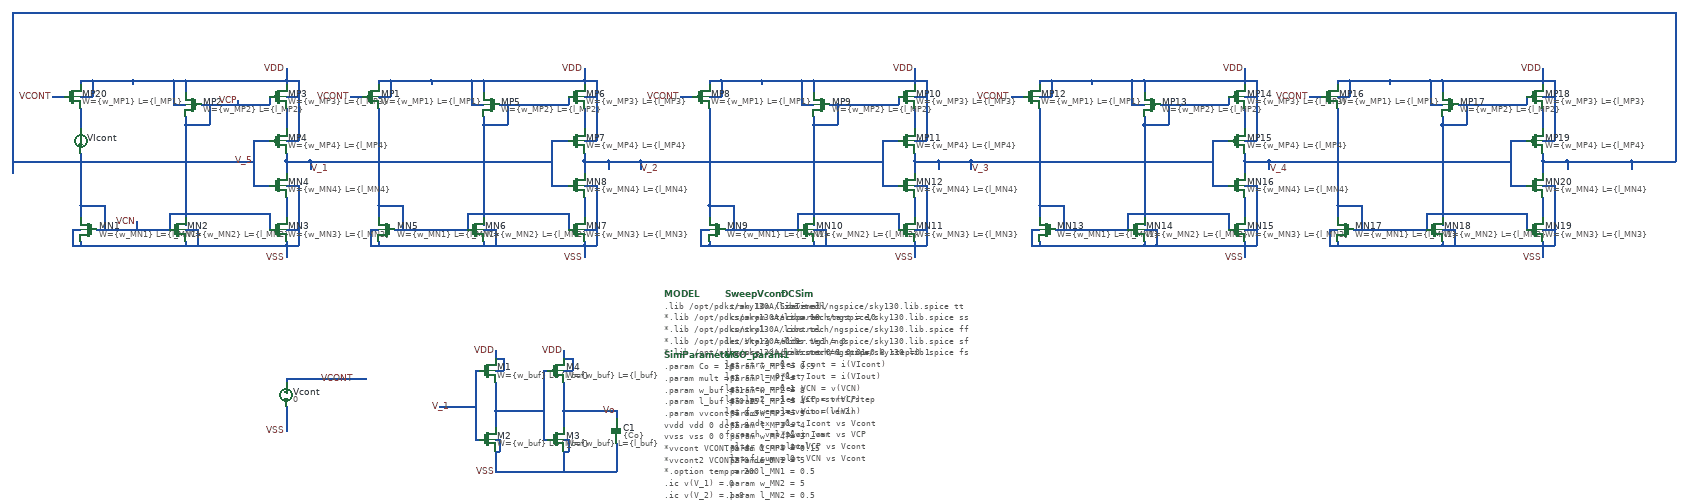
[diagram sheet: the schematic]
v {xschem version=3.4.5 file_version=1.2
}
G {}
K {}
V {}
S {}
E {}
N -2160 -960 -2160 -930 {
lab=VDD}
N -2160 -520 -2160 -490 {
lab=VSS}
N -1990 -190 -1960 -190 {
lab=VCONT}
N -1780 -120 -1750 -120 {
lab=V_1}
N -1750 -120 -1720 -120 {
lab=V_1}
N -1720 -120 -1690 -120 {
lab=V_1}
N -2160 -190 -1990 -190 {
lab=VCONT}
N -2160 -190 -2160 -180 {
lab=VCONT}
N -2160 -120 -2160 -80 {
lab=VSS}
N -2160 -80 -2160 -60 {
lab=VSS}
N -2240 -780 -2200 -780 { lab=V_5}
N -2240 -780 -2240 -670 { lab=V_5}
N -2240 -670 -2200 -670 { lab=V_5}
N -2160 -730 -2160 -700 { lab=V_1}
N -2160 -860 -2160 -810 { lab=#net1}
N -2160 -780 -2130 -780 { lab=VDD}
N -2160 -670 -2130 -670 { lab=VSS}
N -2130 -670 -2130 -560 { lab=VSS}
N -2160 -640 -2160 -590 { lab=#net2}
N -2160 -730 -2100 -730 { lab=V_1}
N -2160 -520 -2160 -510 {
lab=VSS}
N -2160 -930 -2160 -920 {
lab=VDD}
N -2160 -930 -2130 -930 {
lab=VDD}
N -2130 -890 -2130 -780 {
lab=VDD}
N -2160 -890 -2130 -890 {
lab=VDD}
N -2160 -520 -2130 -520 {
lab=VSS}
N -2130 -560 -2130 -520 {
lab=VSS}
N -2160 -560 -2130 -560 {
lab=VSS}
N -2350 -870 -2200 -870 {
lab=VCP}
N -2410 -910 -2410 -900 {
lab=VDD}
N -2410 -930 -2160 -930 {
lab=VDD}
N -2410 -820 -2410 -570 {
lab=VCP}
N -2380 -520 -2160 -520 {
lab=VSS}
N -2410 -530 -2410 -520 {
lab=VSS}
N -2610 -560 -2450 -560 {
lab=VCN}
N -2670 -520 -2410 -520 {
lab=VSS}
N -2670 -530 -2670 -520 {
lab=VSS}
N -2670 -620 -2670 -590 {
lab=VCN}
N -2440 -930 -2410 -930 {
lab=VDD}
N -2670 -930 -2670 -920 {
lab=VDD}
N -2610 -620 -2610 -560 {
lab=VCN}
N -2670 -620 -2610 -620 {
lab=VCN}
N -2410 -820 -2350 -820 {
lab=VCP}
N -2350 -870 -2350 -820 {
lab=VCP}
N -2740 -890 -2710 -890 {
lab=VCONT}
N -2410 -560 -2380 -560 {
lab=VSS}
N -2380 -560 -2380 -520 {
lab=VSS}
N -2450 -600 -2450 -560 {
lab=VCN}
N -2450 -600 -2200 -600 {
lab=VCN}
N -2200 -600 -2200 -560 {
lab=VCN}
N -2690 -560 -2670 -560 {
lab=VSS}
N -2690 -560 -2690 -520 {
lab=VSS}
N -2690 -520 -2670 -520 {
lab=VSS}
N -2670 -890 -2640 -890 {
lab=VDD}
N -2640 -930 -2640 -890 {
lab=VDD}
N -2440 -870 -2410 -870 {
lab=VDD}
N -2440 -910 -2440 -870 {
lab=VDD}
N -2160 -750 -2160 -730 { lab=V_1}
N -2160 -940 -2160 -930 {
lab=VDD}
N -2130 -930 -2130 -890 {
lab=VDD}
N -2160 -530 -2160 -520 {
lab=VSS}
N -2630 -560 -2610 -560 {
lab=VCN}
N -2410 -840 -2410 -820 {
lab=VCP}
N -2370 -870 -2350 -870 {
lab=VCP}
N -2410 -520 -2380 -520 {
lab=VSS}
N -2670 -930 -2640 -930 {
lab=VDD}
N -2510 -930 -2440 -930 {
lab=VDD}
N -2540 -930 -2540 -920 {
lab=VDD}
N -2540 -930 -2510 -930 {
lab=VDD}
N -2640 -930 -2540 -930 {
lab=VDD}
N -2670 -860 -2670 -830 {
lab=#net3}
N -2200 -890 -2200 -870 {
lab=VCP}
N -2440 -930 -2440 -910 {
lab=VDD}
N -2410 -930 -2410 -910 {
lab=VDD}
N -510 -730 -450 -730 { lab=V_3}
N 1120 -730 1180 -730 { lab=V_5}
N -2100 -730 -2100 -710 {
lab=V_1}
N -1280 -730 -1280 -710 {
lab=V_2}
N 1180 -730 1180 -710 {
lab=V_5}
N 1180 -730 1290 -730 {
lab=V_5}
N 1290 -1090 1290 -730 {
lab=V_5}
N -2840 -1100 1290 -1100 {
lab=V_5}
N -2840 -1100 -2840 -700 {
lab=V_5}
N -2840 -730 -2240 -730 {
lab=V_5}
N -1420 -960 -1420 -930 {
lab=VDD}
N -1420 -520 -1420 -490 {
lab=VSS}
N -1500 -780 -1460 -780 { lab=V_1}
N -1500 -780 -1500 -670 { lab=V_1}
N -1500 -670 -1460 -670 { lab=V_1}
N -1420 -730 -1420 -700 { lab=V_2}
N -1420 -860 -1420 -810 { lab=#net4}
N -1420 -780 -1390 -780 { lab=VDD}
N -1420 -670 -1390 -670 { lab=VSS}
N -1390 -670 -1390 -560 { lab=VSS}
N -1420 -640 -1420 -590 { lab=#net5}
N -1420 -730 -1360 -730 { lab=V_2}
N -1420 -520 -1420 -510 {
lab=VSS}
N -1420 -930 -1420 -920 {
lab=VDD}
N -1420 -930 -1390 -930 {
lab=VDD}
N -1390 -890 -1390 -780 {
lab=VDD}
N -1420 -890 -1390 -890 {
lab=VDD}
N -1420 -520 -1390 -520 {
lab=VSS}
N -1390 -560 -1390 -520 {
lab=VSS}
N -1420 -560 -1390 -560 {
lab=VSS}
N -1610 -870 -1460 -870 {
lab=#net6}
N -1670 -910 -1670 -900 {
lab=VDD}
N -1670 -930 -1420 -930 {
lab=VDD}
N -1670 -820 -1670 -570 {
lab=#net6}
N -1640 -520 -1420 -520 {
lab=VSS}
N -1670 -530 -1670 -520 {
lab=VSS}
N -1870 -560 -1710 -560 {
lab=#net7}
N -1930 -520 -1670 -520 {
lab=VSS}
N -1930 -530 -1930 -520 {
lab=VSS}
N -1930 -620 -1930 -590 {
lab=#net7}
N -1700 -930 -1670 -930 {
lab=VDD}
N -1930 -930 -1930 -920 {
lab=VDD}
N -1870 -620 -1870 -560 {
lab=#net7}
N -1930 -620 -1870 -620 {
lab=#net7}
N -1670 -820 -1610 -820 {
lab=#net6}
N -1610 -870 -1610 -820 {
lab=#net6}
N -2000 -890 -1970 -890 {
lab=VCONT}
N -1670 -560 -1640 -560 {
lab=VSS}
N -1640 -560 -1640 -520 {
lab=VSS}
N -1710 -600 -1710 -560 {
lab=#net7}
N -1710 -600 -1460 -600 {
lab=#net7}
N -1460 -600 -1460 -560 {
lab=#net7}
N -1950 -560 -1930 -560 {
lab=VSS}
N -1950 -560 -1950 -520 {
lab=VSS}
N -1950 -520 -1930 -520 {
lab=VSS}
N -1930 -890 -1900 -890 {
lab=VDD}
N -1900 -930 -1900 -890 {
lab=VDD}
N -1700 -870 -1670 -870 {
lab=VDD}
N -1700 -910 -1700 -870 {
lab=VDD}
N -1420 -750 -1420 -730 { lab=V_2}
N -1420 -940 -1420 -930 {
lab=VDD}
N -1390 -930 -1390 -890 {
lab=VDD}
N -1420 -530 -1420 -520 {
lab=VSS}
N -1890 -560 -1870 -560 {
lab=#net7}
N -1930 -830 -1930 -620 {
lab=#net7}
N -1670 -840 -1670 -820 {
lab=#net6}
N -1630 -870 -1610 -870 {
lab=#net6}
N -1670 -520 -1640 -520 {
lab=VSS}
N -1930 -930 -1900 -930 {
lab=VDD}
N -1770 -930 -1700 -930 {
lab=VDD}
N -1800 -930 -1800 -920 {
lab=VDD}
N -1800 -930 -1770 -930 {
lab=VDD}
N -1900 -930 -1800 -930 {
lab=VDD}
N -1930 -860 -1930 -830 {
lab=#net7}
N -1460 -890 -1460 -870 {
lab=#net6}
N -1700 -930 -1700 -910 {
lab=VDD}
N -1670 -930 -1670 -910 {
lab=VDD}
N -1360 -730 -1360 -710 {
lab=V_2}
N -2100 -730 -1500 -730 {
lab=V_1}
N -1360 -730 -1280 -730 {
lab=V_2}
N -460 -730 -460 -710 {
lab=V_3}
N -600 -960 -600 -930 {
lab=VDD}
N -600 -520 -600 -490 {
lab=VSS}
N -680 -780 -640 -780 { lab=V_2}
N -680 -780 -680 -670 { lab=V_2}
N -680 -670 -640 -670 { lab=V_2}
N -600 -730 -600 -700 { lab=V_3}
N -600 -860 -600 -810 { lab=#net8}
N -600 -780 -570 -780 { lab=VDD}
N -600 -670 -570 -670 { lab=VSS}
N -570 -670 -570 -560 { lab=VSS}
N -600 -640 -600 -590 { lab=#net9}
N -600 -730 -540 -730 { lab=V_3}
N -600 -520 -600 -510 {
lab=VSS}
N -600 -930 -600 -920 {
lab=VDD}
N -600 -930 -570 -930 {
lab=VDD}
N -570 -890 -570 -780 {
lab=VDD}
N -600 -890 -570 -890 {
lab=VDD}
N -600 -520 -570 -520 {
lab=VSS}
N -570 -560 -570 -520 {
lab=VSS}
N -600 -560 -570 -560 {
lab=VSS}
N -790 -870 -640 -870 {
lab=#net10}
N -850 -910 -850 -900 {
lab=VDD}
N -850 -930 -600 -930 {
lab=VDD}
N -850 -820 -850 -570 {
lab=#net10}
N -820 -520 -600 -520 {
lab=VSS}
N -850 -530 -850 -520 {
lab=VSS}
N -1050 -560 -890 -560 {
lab=#net11}
N -1110 -520 -850 -520 {
lab=VSS}
N -1110 -530 -1110 -520 {
lab=VSS}
N -1110 -620 -1110 -590 {
lab=#net11}
N -880 -930 -850 -930 {
lab=VDD}
N -1110 -930 -1110 -920 {
lab=VDD}
N -1050 -620 -1050 -560 {
lab=#net11}
N -1110 -620 -1050 -620 {
lab=#net11}
N -850 -820 -790 -820 {
lab=#net10}
N -790 -870 -790 -820 {
lab=#net10}
N -1180 -890 -1150 -890 {
lab=VCONT}
N -850 -560 -820 -560 {
lab=VSS}
N -820 -560 -820 -520 {
lab=VSS}
N -890 -600 -890 -560 {
lab=#net11}
N -890 -600 -640 -600 {
lab=#net11}
N -640 -600 -640 -560 {
lab=#net11}
N -1130 -560 -1110 -560 {
lab=VSS}
N -1130 -560 -1130 -520 {
lab=VSS}
N -1130 -520 -1110 -520 {
lab=VSS}
N -1110 -890 -1080 -890 {
lab=VDD}
N -1080 -930 -1080 -890 {
lab=VDD}
N -880 -870 -850 -870 {
lab=VDD}
N -880 -910 -880 -870 {
lab=VDD}
N -600 -750 -600 -730 { lab=V_3}
N -600 -940 -600 -930 {
lab=VDD}
N -570 -930 -570 -890 {
lab=VDD}
N -600 -530 -600 -520 {
lab=VSS}
N -1070 -560 -1050 -560 {
lab=#net11}
N -1110 -830 -1110 -620 {
lab=#net11}
N -850 -840 -850 -820 {
lab=#net10}
N -810 -870 -790 -870 {
lab=#net10}
N -850 -520 -820 -520 {
lab=VSS}
N -1110 -930 -1080 -930 {
lab=VDD}
N -950 -930 -880 -930 {
lab=VDD}
N -980 -930 -980 -920 {
lab=VDD}
N -980 -930 -950 -930 {
lab=VDD}
N -1080 -930 -980 -930 {
lab=VDD}
N -1110 -860 -1110 -830 {
lab=#net11}
N -640 -890 -640 -870 {
lab=#net10}
N -880 -930 -880 -910 {
lab=VDD}
N -850 -930 -850 -910 {
lab=VDD}
N -540 -730 -540 -710 {
lab=V_3}
N -1280 -730 -680 -730 {
lab=V_2}
N -540 -730 -460 -730 {
lab=V_3}
N 220 -960 220 -930 {
lab=VDD}
N 220 -520 220 -490 {
lab=VSS}
N 140 -780 180 -780 { lab=V_3}
N 140 -780 140 -670 { lab=V_3}
N 140 -670 180 -670 { lab=V_3}
N 220 -730 220 -700 { lab=V_4}
N 220 -860 220 -810 { lab=#net12}
N 220 -780 250 -780 { lab=VDD}
N 220 -670 250 -670 { lab=VSS}
N 250 -670 250 -560 { lab=VSS}
N 220 -640 220 -590 { lab=#net13}
N 220 -730 280 -730 { lab=V_4}
N 220 -520 220 -510 {
lab=VSS}
N 220 -930 220 -920 {
lab=VDD}
N 220 -930 250 -930 {
lab=VDD}
N 250 -890 250 -780 {
lab=VDD}
N 220 -890 250 -890 {
lab=VDD}
N 220 -520 250 -520 {
lab=VSS}
N 250 -560 250 -520 {
lab=VSS}
N 220 -560 250 -560 {
lab=VSS}
N 30 -870 180 -870 {
lab=#net14}
N -30 -910 -30 -900 {
lab=VDD}
N -30 -930 220 -930 {
lab=VDD}
N -30 -820 -30 -570 {
lab=#net14}
N 0 -520 220 -520 {
lab=VSS}
N -30 -530 -30 -520 {
lab=VSS}
N -230 -560 -70 -560 {
lab=#net15}
N -290 -520 -30 -520 {
lab=VSS}
N -290 -530 -290 -520 {
lab=VSS}
N -290 -620 -290 -590 {
lab=#net15}
N -60 -930 -30 -930 {
lab=VDD}
N -290 -930 -290 -920 {
lab=VDD}
N -230 -620 -230 -560 {
lab=#net15}
N -290 -620 -230 -620 {
lab=#net15}
N -30 -820 30 -820 {
lab=#net14}
N 30 -870 30 -820 {
lab=#net14}
N -360 -890 -330 -890 {
lab=VCONT}
N -30 -560 0 -560 {
lab=VSS}
N 0 -560 0 -520 {
lab=VSS}
N -70 -600 -70 -560 {
lab=#net15}
N -70 -600 180 -600 {
lab=#net15}
N 180 -600 180 -560 {
lab=#net15}
N -310 -560 -290 -560 {
lab=VSS}
N -310 -560 -310 -520 {
lab=VSS}
N -310 -520 -290 -520 {
lab=VSS}
N -290 -890 -260 -890 {
lab=VDD}
N -260 -930 -260 -890 {
lab=VDD}
N -60 -870 -30 -870 {
lab=VDD}
N -60 -910 -60 -870 {
lab=VDD}
N 220 -750 220 -730 { lab=V_4}
N 220 -940 220 -930 {
lab=VDD}
N 250 -930 250 -890 {
lab=VDD}
N 220 -530 220 -520 {
lab=VSS}
N -250 -560 -230 -560 {
lab=#net15}
N -290 -830 -290 -620 {
lab=#net15}
N -30 -840 -30 -820 {
lab=#net14}
N 10 -870 30 -870 {
lab=#net14}
N -30 -520 0 -520 {
lab=VSS}
N -290 -930 -260 -930 {
lab=VDD}
N -130 -930 -60 -930 {
lab=VDD}
N -160 -930 -160 -920 {
lab=VDD}
N -160 -930 -130 -930 {
lab=VDD}
N -260 -930 -160 -930 {
lab=VDD}
N -290 -860 -290 -830 {
lab=#net15}
N 180 -890 180 -870 {
lab=#net14}
N -60 -930 -60 -910 {
lab=VDD}
N -30 -930 -30 -910 {
lab=VDD}
N 280 -730 280 -710 {
lab=V_4}
N -460 -730 140 -730 {
lab=V_3}
N 960 -960 960 -930 {
lab=VDD}
N 960 -520 960 -490 {
lab=VSS}
N 880 -780 920 -780 { lab=V_4}
N 880 -780 880 -670 { lab=V_4}
N 880 -670 920 -670 { lab=V_4}
N 960 -730 960 -700 { lab=V_5}
N 960 -860 960 -810 { lab=#net16}
N 960 -780 990 -780 { lab=VDD}
N 960 -670 990 -670 { lab=VSS}
N 990 -670 990 -560 { lab=VSS}
N 960 -640 960 -590 { lab=#net17}
N 960 -730 1020 -730 { lab=V_5}
N 960 -520 960 -510 {
lab=VSS}
N 960 -930 960 -920 {
lab=VDD}
N 960 -930 990 -930 {
lab=VDD}
N 990 -890 990 -780 {
lab=VDD}
N 960 -890 990 -890 {
lab=VDD}
N 960 -520 990 -520 {
lab=VSS}
N 990 -560 990 -520 {
lab=VSS}
N 960 -560 990 -560 {
lab=VSS}
N 770 -870 920 -870 {
lab=#net18}
N 710 -910 710 -900 {
lab=VDD}
N 710 -930 960 -930 {
lab=VDD}
N 710 -820 710 -570 {
lab=#net18}
N 740 -520 960 -520 {
lab=VSS}
N 710 -530 710 -520 {
lab=VSS}
N 510 -560 670 -560 {
lab=#net19}
N 450 -520 710 -520 {
lab=VSS}
N 450 -530 450 -520 {
lab=VSS}
N 450 -620 450 -590 {
lab=#net19}
N 680 -930 710 -930 {
lab=VDD}
N 450 -930 450 -920 {
lab=VDD}
N 510 -620 510 -560 {
lab=#net19}
N 450 -620 510 -620 {
lab=#net19}
N 710 -820 770 -820 {
lab=#net18}
N 770 -870 770 -820 {
lab=#net18}
N 380 -890 410 -890 {
lab=VCONT}
N 710 -560 740 -560 {
lab=VSS}
N 740 -560 740 -520 {
lab=VSS}
N 670 -600 670 -560 {
lab=#net19}
N 670 -600 920 -600 {
lab=#net19}
N 920 -600 920 -560 {
lab=#net19}
N 430 -560 450 -560 {
lab=VSS}
N 430 -560 430 -520 {
lab=VSS}
N 430 -520 450 -520 {
lab=VSS}
N 450 -890 480 -890 {
lab=VDD}
N 480 -930 480 -890 {
lab=VDD}
N 680 -870 710 -870 {
lab=VDD}
N 680 -910 680 -870 {
lab=VDD}
N 960 -750 960 -730 { lab=V_5}
N 960 -940 960 -930 {
lab=VDD}
N 990 -930 990 -890 {
lab=VDD}
N 960 -530 960 -520 {
lab=VSS}
N 490 -560 510 -560 {
lab=#net19}
N 450 -830 450 -620 {
lab=#net19}
N 710 -840 710 -820 {
lab=#net18}
N 750 -870 770 -870 {
lab=#net18}
N 710 -520 740 -520 {
lab=VSS}
N 450 -930 480 -930 {
lab=VDD}
N 610 -930 680 -930 {
lab=VDD}
N 580 -930 580 -920 {
lab=VDD}
N 580 -930 610 -930 {
lab=VDD}
N 480 -930 580 -930 {
lab=VDD}
N 450 -860 450 -830 {
lab=#net19}
N 920 -890 920 -870 {
lab=#net18}
N 680 -930 680 -910 {
lab=VDD}
N 710 -930 710 -910 {
lab=VDD}
N 1020 -730 1020 -710 {
lab=V_5}
N 280 -730 880 -730 {
lab=V_4}
N 1020 -730 1120 -730 {
lab=V_5}
N 1290 -1100 1290 -1070 {
lab=V_5}
N -1640 -110 -1640 -70 {
lab=#net20}
N -1640 -180 -1640 -110 {
lab=#net20}
N -1640 -40 -1630 -40 {
lab=VSS}
N -1630 -40 -1630 -10 {
lab=VSS}
N -1640 -10 -1630 -10 {
lab=VSS}
N -1640 -210 -1620 -210 {
lab=VDD}
N -1620 -240 -1620 -210 {
lab=VDD}
N -1640 -240 -1620 -240 {
lab=VDD}
N -1640 -110 -1630 -110 {
lab=#net20}
N -1690 -210 -1680 -210 {
lab=V_1}
N -1690 -210 -1690 -40 {
lab=V_1}
N -1690 -40 -1680 -40 {
lab=V_1}
N -1640 -10 -1640 40 {
lab=VSS}
N -1640 -260 -1640 -240 {
lab=VDD}
N -1340 -30 -1340 40 {
lab=VSS}
N -1340 -110 -1340 -90 {
lab=Vo}
N -1470 -110 -1470 -70 {
lab=Vo}
N -1470 -180 -1470 -110 {
lab=Vo}
N -1470 -40 -1460 -40 {
lab=VSS}
N -1460 -40 -1460 -10 {
lab=VSS}
N -1470 -10 -1460 -10 {
lab=VSS}
N -1470 -210 -1450 -210 {
lab=VDD}
N -1450 -240 -1450 -210 {
lab=VDD}
N -1470 -240 -1450 -240 {
lab=VDD}
N -1470 -110 -1460 -110 {
lab=Vo}
N -1520 -210 -1510 -210 {
lab=#net20}
N -1520 -210 -1520 -40 {
lab=#net20}
N -1520 -40 -1510 -40 {
lab=#net20}
N -1470 -10 -1470 40 {
lab=VSS}
N -1470 -260 -1470 -240 {
lab=VDD}
N -1630 -110 -1520 -110 {
lab=#net20}
N -1470 -110 -1340 -110 {
lab=Vo}
N -1640 40 -1340 40 {
lab=VSS}
N -2670 -830 -2670 -810 {
lab=#net3}
N -2670 -750 -2670 -620 {
lab=VCN}
N -2530 -580 -2530 -560 {
lab=VCN}
N -2280 -880 -2280 -870 {
lab=VCP}
C {devices/lab_pin.sym} -2160 -960 1 0 {name=p4 sig_type=std_logic lab=VDD}
C {devices/lab_pin.sym} -2160 -490 3 0 {name=p5 sig_type=std_logic lab=VSS}
C {devices/lab_pin.sym} -1990 -190 1 0 {name=p6 sig_type=std_logic lab=VCONT}
C {devices/lab_pin.sym} -1750 -120 1 0 {name=p7 sig_type=std_logic lab=V_1}
C {vsource.sym} -2160 -150 0 0 {name=Vcont value=0 savecurrent=false}
C {devices/lab_pin.sym} -2160 -60 3 0 {name=p11 sig_type=std_logic lab=VSS}
C {sky130_fd_pr/pfet_01v8.sym} -2690 -890 0 0 {name=MP20
W= \{w_MP1\}
L= \{l_MP1\}
nf=1
mult=1
ad="'int((nf+1)/2) * W/nf * 0.29'" 
pd="'2*int((nf+1)/2) * (W/nf + 0.29)'"
as="'int((nf+2)/2) * W/nf * 0.29'" 
ps="'2*int((nf+2)/2) * (W/nf + 0.29)'"
nrd="'0.29 / W'" nrs="'0.29 / W'"
sa=0 sb=0 sd=0
model=pfet_01v8
spiceprefix=X
}
C {sky130_fd_pr/pfet_01v8.sym} -2390 -870 0 1 {name=MP2
*W= 8
W = \{w_MP2\}
*L= 4
L = \{l_MP2\}
nf=1
mult=1
ad="'int((nf+1)/2) * W/nf * 0.29'" 
pd="'2*int((nf+1)/2) * (W/nf + 0.29)'"
as="'int((nf+2)/2) * W/nf * 0.29'" 
ps="'2*int((nf+2)/2) * (W/nf + 0.29)'"
nrd="'0.29 / W'" nrs="'0.29 / W'"
sa=0 sb=0 sd=0
model=pfet_01v8
spiceprefix=X
}
C {sky130_fd_pr/pfet_01v8.sym} -2180 -890 0 0 {name=MP3
*W=5
W = \{w_MP3\}
*L=4
L = \{l_MP3\}
nf=1
mult=1
ad="'int((nf+1)/2) * W/nf * 0.29'" 
pd="'2*int((nf+1)/2) * (W/nf + 0.29)'"
as="'int((nf+2)/2) * W/nf * 0.29'" 
ps="'2*int((nf+2)/2) * (W/nf + 0.29)'"
nrd="'0.29 / W'" nrs="'0.29 / W'"
sa=0 sb=0 sd=0
model=pfet_01v8
spiceprefix=X
}
C {sky130_fd_pr/pfet_01v8.sym} -2180 -780 0 0 {name=MP4
*W=5
W = \{w_MP4\}
L = \{l_MP4\}
*L=5
nf=1
mult=1
ad="'int((nf+1)/2) * W/nf * 0.29'" 
pd="'2*int((nf+1)/2) * (W/nf + 0.29)'"
as="'int((nf+2)/2) * W/nf * 0.29'" 
ps="'2*int((nf+2)/2) * (W/nf + 0.29)'"
nrd="'0.29 / W'" nrs="'0.29 / W'"
sa=0 sb=0 sd=0
model=pfet_01v8
spiceprefix=X
}
C {sky130_fd_pr/nfet_01v8.sym} -2650 -560 0 1 {name=MN1
*W=5
W = \{w_MN1\}
*L=0.5
L = \{l_MN1\}
nf=1
mult=1
ad="'int((nf+1)/2) * W/nf * 0.29'" 
pd="'2*int((nf+1)/2) * (W/nf + 0.29)'"
as="'int((nf+2)/2) * W/nf * 0.29'" 
ps="'2*int((nf+2)/2) * (W/nf + 0.29)'"
nrd="'0.29 / W'" nrs="'0.29 / W'"
sa=0 sb=0 sd=0
model=nfet_01v8
spiceprefix=X
}
C {sky130_fd_pr/nfet_01v8.sym} -2430 -560 0 0 {name=MN2
*W=5
W = \{w_MN2\}
*L=0.5
L = \{l_MN2\}
nf=1
mult=1
ad="'int((nf+1)/2) * W/nf * 0.29'" 
pd="'2*int((nf+1)/2) * (W/nf + 0.29)'"
as="'int((nf+2)/2) * W/nf * 0.29'" 
ps="'2*int((nf+2)/2) * (W/nf + 0.29)'"
nrd="'0.29 / W'" nrs="'0.29 / W'"
sa=0 sb=0 sd=0
model=nfet_01v8
spiceprefix=X
}
C {sky130_fd_pr/nfet_01v8.sym} -2180 -560 0 0 {name=MN3
*W=3
W = \{w_MN3\}
*L=0.5
L = \{l_MN3\}
nf=1
mult=1
ad="'int((nf+1)/2) * W/nf * 0.29'" 
pd="'2*int((nf+1)/2) * (W/nf + 0.29)'"
as="'int((nf+2)/2) * W/nf * 0.29'" 
ps="'2*int((nf+2)/2) * (W/nf + 0.29)'"
nrd="'0.29 / W'" nrs="'0.29 / W'"
sa=0 sb=0 sd=0
model=nfet_01v8
spiceprefix=X
}
C {sky130_fd_pr/nfet_01v8.sym} -2180 -670 0 0 {name=MN4
*W=2
W = \{w_MN4\}
*L=5
L = \{l_MN4\}
nf=1
mult=1
ad="'int((nf+1)/2) * W/nf * 0.29'" 
pd="'2*int((nf+1)/2) * (W/nf + 0.29)'"
as="'int((nf+2)/2) * W/nf * 0.29'" 
ps="'2*int((nf+2)/2) * (W/nf + 0.29)'"
nrd="'0.29 / W'" nrs="'0.29 / W'"
sa=0 sb=0 sd=0
model=nfet_01v8
spiceprefix=X
}
C {devices/lab_pin.sym} -2740 -890 0 0 {name=p27 sig_type=std_logic lab=VCONT}
C {devices/lab_pin.sym} -2100 -710 2 0 {name=p21 sig_type=std_logic lab=V_1}
C {devices/lab_pin.sym} -2240 -730 0 0 {name=p22 sig_type=std_logic lab=V_5}
C {devices/lab_pin.sym} -1280 -710 2 0 {name=p29 sig_type=std_logic lab=V_2}
C {devices/lab_pin.sym} -460 -710 2 0 {name=p35 sig_type=std_logic lab=V_3}
C {devices/lab_pin.sym} 280 -710 2 0 {name=p41 sig_type=std_logic lab=V_4}
C {devices/lab_pin.sym} -1420 -960 1 0 {name=p1 sig_type=std_logic lab=VDD}
C {devices/lab_pin.sym} -1420 -490 3 0 {name=p12 sig_type=std_logic lab=VSS}
C {sky130_fd_pr/pfet_01v8.sym} -1950 -890 0 0 {name=MP1
W= \{w_MP1\}
L= \{l_MP1\}
nf=1
mult=1
ad="'int((nf+1)/2) * W/nf * 0.29'" 
pd="'2*int((nf+1)/2) * (W/nf + 0.29)'"
as="'int((nf+2)/2) * W/nf * 0.29'" 
ps="'2*int((nf+2)/2) * (W/nf + 0.29)'"
nrd="'0.29 / W'" nrs="'0.29 / W'"
sa=0 sb=0 sd=0
model=pfet_01v8
spiceprefix=X
}
C {sky130_fd_pr/pfet_01v8.sym} -1650 -870 0 1 {name=MP5
*W= 8
W = \{w_MP2\}
*L= 4
L = \{l_MP2\}
nf=1
mult=1
ad="'int((nf+1)/2) * W/nf * 0.29'" 
pd="'2*int((nf+1)/2) * (W/nf + 0.29)'"
as="'int((nf+2)/2) * W/nf * 0.29'" 
ps="'2*int((nf+2)/2) * (W/nf + 0.29)'"
nrd="'0.29 / W'" nrs="'0.29 / W'"
sa=0 sb=0 sd=0
model=pfet_01v8
spiceprefix=X
}
C {sky130_fd_pr/pfet_01v8.sym} -1440 -890 0 0 {name=MP6
*W=5
W = \{w_MP3\}
*L=4
L = \{l_MP3\}
nf=1
mult=1
ad="'int((nf+1)/2) * W/nf * 0.29'" 
pd="'2*int((nf+1)/2) * (W/nf + 0.29)'"
as="'int((nf+2)/2) * W/nf * 0.29'" 
ps="'2*int((nf+2)/2) * (W/nf + 0.29)'"
nrd="'0.29 / W'" nrs="'0.29 / W'"
sa=0 sb=0 sd=0
model=pfet_01v8
spiceprefix=X
}
C {sky130_fd_pr/pfet_01v8.sym} -1440 -780 0 0 {name=MP7
*W=5
W = \{w_MP4\}
L = \{l_MP4\}
*L=5
nf=1
mult=1
ad="'int((nf+1)/2) * W/nf * 0.29'" 
pd="'2*int((nf+1)/2) * (W/nf + 0.29)'"
as="'int((nf+2)/2) * W/nf * 0.29'" 
ps="'2*int((nf+2)/2) * (W/nf + 0.29)'"
nrd="'0.29 / W'" nrs="'0.29 / W'"
sa=0 sb=0 sd=0
model=pfet_01v8
spiceprefix=X
}
C {sky130_fd_pr/nfet_01v8.sym} -1910 -560 0 1 {name=MN5
*W=5
W = \{w_MN1\}
*L=0.5
L = \{l_MN1\}
nf=1
mult=1
ad="'int((nf+1)/2) * W/nf * 0.29'" 
pd="'2*int((nf+1)/2) * (W/nf + 0.29)'"
as="'int((nf+2)/2) * W/nf * 0.29'" 
ps="'2*int((nf+2)/2) * (W/nf + 0.29)'"
nrd="'0.29 / W'" nrs="'0.29 / W'"
sa=0 sb=0 sd=0
model=nfet_01v8
spiceprefix=X
}
C {sky130_fd_pr/nfet_01v8.sym} -1690 -560 0 0 {name=MN6
*W=5
W = \{w_MN2\}
*L=0.5
L = \{l_MN2\}
nf=1
mult=1
ad="'int((nf+1)/2) * W/nf * 0.29'" 
pd="'2*int((nf+1)/2) * (W/nf + 0.29)'"
as="'int((nf+2)/2) * W/nf * 0.29'" 
ps="'2*int((nf+2)/2) * (W/nf + 0.29)'"
nrd="'0.29 / W'" nrs="'0.29 / W'"
sa=0 sb=0 sd=0
model=nfet_01v8
spiceprefix=X
}
C {sky130_fd_pr/nfet_01v8.sym} -1440 -560 0 0 {name=MN7
*W=3
W = \{w_MN3\}
*L=0.5
L = \{l_MN3\}
nf=1
mult=1
ad="'int((nf+1)/2) * W/nf * 0.29'" 
pd="'2*int((nf+1)/2) * (W/nf + 0.29)'"
as="'int((nf+2)/2) * W/nf * 0.29'" 
ps="'2*int((nf+2)/2) * (W/nf + 0.29)'"
nrd="'0.29 / W'" nrs="'0.29 / W'"
sa=0 sb=0 sd=0
model=nfet_01v8
spiceprefix=X
}
C {sky130_fd_pr/nfet_01v8.sym} -1440 -670 0 0 {name=MN8
*W=2
W = \{w_MN4\}
*L=5
L = \{l_MN4\}
nf=1
mult=1
ad="'int((nf+1)/2) * W/nf * 0.29'" 
pd="'2*int((nf+1)/2) * (W/nf + 0.29)'"
as="'int((nf+2)/2) * W/nf * 0.29'" 
ps="'2*int((nf+2)/2) * (W/nf + 0.29)'"
nrd="'0.29 / W'" nrs="'0.29 / W'"
sa=0 sb=0 sd=0
model=nfet_01v8
spiceprefix=X
}
C {devices/lab_pin.sym} -2000 -890 0 0 {name=p13 sig_type=std_logic lab=VCONT}
C {devices/lab_pin.sym} -600 -960 1 0 {name=p15 sig_type=std_logic lab=VDD}
C {devices/lab_pin.sym} -600 -490 3 0 {name=p16 sig_type=std_logic lab=VSS}
C {sky130_fd_pr/pfet_01v8.sym} -1130 -890 0 0 {name=MP8
W= \{w_MP1\}
L= \{l_MP1\}
nf=1
mult=1
ad="'int((nf+1)/2) * W/nf * 0.29'" 
pd="'2*int((nf+1)/2) * (W/nf + 0.29)'"
as="'int((nf+2)/2) * W/nf * 0.29'" 
ps="'2*int((nf+2)/2) * (W/nf + 0.29)'"
nrd="'0.29 / W'" nrs="'0.29 / W'"
sa=0 sb=0 sd=0
model=pfet_01v8
spiceprefix=X
}
C {sky130_fd_pr/pfet_01v8.sym} -830 -870 0 1 {name=MP9
*W= 8
W = \{w_MP2\}
*L= 4
L = \{l_MP2\}
nf=1
mult=1
ad="'int((nf+1)/2) * W/nf * 0.29'" 
pd="'2*int((nf+1)/2) * (W/nf + 0.29)'"
as="'int((nf+2)/2) * W/nf * 0.29'" 
ps="'2*int((nf+2)/2) * (W/nf + 0.29)'"
nrd="'0.29 / W'" nrs="'0.29 / W'"
sa=0 sb=0 sd=0
model=pfet_01v8
spiceprefix=X
}
C {sky130_fd_pr/pfet_01v8.sym} -620 -890 0 0 {name=MP10
*W=5
W = \{w_MP3\}
*L=4
L = \{l_MP3\}
nf=1
mult=1
ad="'int((nf+1)/2) * W/nf * 0.29'" 
pd="'2*int((nf+1)/2) * (W/nf + 0.29)'"
as="'int((nf+2)/2) * W/nf * 0.29'" 
ps="'2*int((nf+2)/2) * (W/nf + 0.29)'"
nrd="'0.29 / W'" nrs="'0.29 / W'"
sa=0 sb=0 sd=0
model=pfet_01v8
spiceprefix=X
}
C {sky130_fd_pr/pfet_01v8.sym} -620 -780 0 0 {name=MP11
*W=5
W = \{w_MP4\}
L = \{l_MP4\}
*L=5
nf=1
mult=1
ad="'int((nf+1)/2) * W/nf * 0.29'" 
pd="'2*int((nf+1)/2) * (W/nf + 0.29)'"
as="'int((nf+2)/2) * W/nf * 0.29'" 
ps="'2*int((nf+2)/2) * (W/nf + 0.29)'"
nrd="'0.29 / W'" nrs="'0.29 / W'"
sa=0 sb=0 sd=0
model=pfet_01v8
spiceprefix=X
}
C {sky130_fd_pr/nfet_01v8.sym} -1090 -560 0 1 {name=MN9
*W=5
W = \{w_MN1\}
*L=0.5
L = \{l_MN1\}
nf=1
mult=1
ad="'int((nf+1)/2) * W/nf * 0.29'" 
pd="'2*int((nf+1)/2) * (W/nf + 0.29)'"
as="'int((nf+2)/2) * W/nf * 0.29'" 
ps="'2*int((nf+2)/2) * (W/nf + 0.29)'"
nrd="'0.29 / W'" nrs="'0.29 / W'"
sa=0 sb=0 sd=0
model=nfet_01v8
spiceprefix=X
}
C {sky130_fd_pr/nfet_01v8.sym} -870 -560 0 0 {name=MN10
*W=5
W = \{w_MN2\}
*L=0.5
L = \{l_MN2\}
nf=1
mult=1
ad="'int((nf+1)/2) * W/nf * 0.29'" 
pd="'2*int((nf+1)/2) * (W/nf + 0.29)'"
as="'int((nf+2)/2) * W/nf * 0.29'" 
ps="'2*int((nf+2)/2) * (W/nf + 0.29)'"
nrd="'0.29 / W'" nrs="'0.29 / W'"
sa=0 sb=0 sd=0
model=nfet_01v8
spiceprefix=X
}
C {sky130_fd_pr/nfet_01v8.sym} -620 -560 0 0 {name=MN11
*W=3
W = \{w_MN3\}
*L=0.5
L = \{l_MN3\}
nf=1
mult=1
ad="'int((nf+1)/2) * W/nf * 0.29'" 
pd="'2*int((nf+1)/2) * (W/nf + 0.29)'"
as="'int((nf+2)/2) * W/nf * 0.29'" 
ps="'2*int((nf+2)/2) * (W/nf + 0.29)'"
nrd="'0.29 / W'" nrs="'0.29 / W'"
sa=0 sb=0 sd=0
model=nfet_01v8
spiceprefix=X
}
C {sky130_fd_pr/nfet_01v8.sym} -620 -670 0 0 {name=MN12
*W=2
W = \{w_MN4\}
*L=5
L = \{l_MN4\}
nf=1
mult=1
ad="'int((nf+1)/2) * W/nf * 0.29'" 
pd="'2*int((nf+1)/2) * (W/nf + 0.29)'"
as="'int((nf+2)/2) * W/nf * 0.29'" 
ps="'2*int((nf+2)/2) * (W/nf + 0.29)'"
nrd="'0.29 / W'" nrs="'0.29 / W'"
sa=0 sb=0 sd=0
model=nfet_01v8
spiceprefix=X
}
C {devices/lab_pin.sym} -1180 -890 0 0 {name=p17 sig_type=std_logic lab=VCONT}
C {devices/lab_pin.sym} 220 -960 1 0 {name=p18 sig_type=std_logic lab=VDD}
C {devices/lab_pin.sym} 220 -490 3 0 {name=p19 sig_type=std_logic lab=VSS}
C {sky130_fd_pr/pfet_01v8.sym} -310 -890 0 0 {name=MP12
W= \{w_MP1\}
L= \{l_MP1\}
nf=1
mult=1
ad="'int((nf+1)/2) * W/nf * 0.29'" 
pd="'2*int((nf+1)/2) * (W/nf + 0.29)'"
as="'int((nf+2)/2) * W/nf * 0.29'" 
ps="'2*int((nf+2)/2) * (W/nf + 0.29)'"
nrd="'0.29 / W'" nrs="'0.29 / W'"
sa=0 sb=0 sd=0
model=pfet_01v8
spiceprefix=X
}
C {sky130_fd_pr/pfet_01v8.sym} -10 -870 0 1 {name=MP13
*W= 8
W = \{w_MP2\}
*L= 4
L = \{l_MP2\}
nf=1
mult=1
ad="'int((nf+1)/2) * W/nf * 0.29'" 
pd="'2*int((nf+1)/2) * (W/nf + 0.29)'"
as="'int((nf+2)/2) * W/nf * 0.29'" 
ps="'2*int((nf+2)/2) * (W/nf + 0.29)'"
nrd="'0.29 / W'" nrs="'0.29 / W'"
sa=0 sb=0 sd=0
model=pfet_01v8
spiceprefix=X
}
C {sky130_fd_pr/pfet_01v8.sym} 200 -890 0 0 {name=MP14
*W=5
W = \{w_MP3\}
*L=4
L = \{l_MP3\}
nf=1
mult=1
ad="'int((nf+1)/2) * W/nf * 0.29'" 
pd="'2*int((nf+1)/2) * (W/nf + 0.29)'"
as="'int((nf+2)/2) * W/nf * 0.29'" 
ps="'2*int((nf+2)/2) * (W/nf + 0.29)'"
nrd="'0.29 / W'" nrs="'0.29 / W'"
sa=0 sb=0 sd=0
model=pfet_01v8
spiceprefix=X
}
C {sky130_fd_pr/pfet_01v8.sym} 200 -780 0 0 {name=MP15
*W=5
W = \{w_MP4\}
L = \{l_MP4\}
*L=5
nf=1
mult=1
ad="'int((nf+1)/2) * W/nf * 0.29'" 
pd="'2*int((nf+1)/2) * (W/nf + 0.29)'"
as="'int((nf+2)/2) * W/nf * 0.29'" 
ps="'2*int((nf+2)/2) * (W/nf + 0.29)'"
nrd="'0.29 / W'" nrs="'0.29 / W'"
sa=0 sb=0 sd=0
model=pfet_01v8
spiceprefix=X
}
C {sky130_fd_pr/nfet_01v8.sym} -270 -560 0 1 {name=MN13
*W=5
W = \{w_MN1\}
*L=0.5
L = \{l_MN1\}
nf=1
mult=1
ad="'int((nf+1)/2) * W/nf * 0.29'" 
pd="'2*int((nf+1)/2) * (W/nf + 0.29)'"
as="'int((nf+2)/2) * W/nf * 0.29'" 
ps="'2*int((nf+2)/2) * (W/nf + 0.29)'"
nrd="'0.29 / W'" nrs="'0.29 / W'"
sa=0 sb=0 sd=0
model=nfet_01v8
spiceprefix=X
}
C {sky130_fd_pr/nfet_01v8.sym} -50 -560 0 0 {name=MN14
*W=5
W = \{w_MN2\}
*L=0.5
L = \{l_MN2\}
nf=1
mult=1
ad="'int((nf+1)/2) * W/nf * 0.29'" 
pd="'2*int((nf+1)/2) * (W/nf + 0.29)'"
as="'int((nf+2)/2) * W/nf * 0.29'" 
ps="'2*int((nf+2)/2) * (W/nf + 0.29)'"
nrd="'0.29 / W'" nrs="'0.29 / W'"
sa=0 sb=0 sd=0
model=nfet_01v8
spiceprefix=X
}
C {sky130_fd_pr/nfet_01v8.sym} 200 -560 0 0 {name=MN15
*W=3
W = \{w_MN3\}
*L=0.5
L = \{l_MN3\}
nf=1
mult=1
ad="'int((nf+1)/2) * W/nf * 0.29'" 
pd="'2*int((nf+1)/2) * (W/nf + 0.29)'"
as="'int((nf+2)/2) * W/nf * 0.29'" 
ps="'2*int((nf+2)/2) * (W/nf + 0.29)'"
nrd="'0.29 / W'" nrs="'0.29 / W'"
sa=0 sb=0 sd=0
model=nfet_01v8
spiceprefix=X
}
C {sky130_fd_pr/nfet_01v8.sym} 200 -670 0 0 {name=MN16
*W=2
W = \{w_MN4\}
*L=5
L = \{l_MN4\}
nf=1
mult=1
ad="'int((nf+1)/2) * W/nf * 0.29'" 
pd="'2*int((nf+1)/2) * (W/nf + 0.29)'"
as="'int((nf+2)/2) * W/nf * 0.29'" 
ps="'2*int((nf+2)/2) * (W/nf + 0.29)'"
nrd="'0.29 / W'" nrs="'0.29 / W'"
sa=0 sb=0 sd=0
model=nfet_01v8
spiceprefix=X
}
C {devices/lab_pin.sym} -360 -890 0 0 {name=p20 sig_type=std_logic lab=VCONT}
C {devices/lab_pin.sym} 960 -960 1 0 {name=p23 sig_type=std_logic lab=VDD}
C {devices/lab_pin.sym} 960 -490 3 0 {name=p24 sig_type=std_logic lab=VSS}
C {sky130_fd_pr/pfet_01v8.sym} 430 -890 0 0 {name=MP16
W= \{w_MP1\}
L= \{l_MP1\}
nf=1
mult=1
ad="'int((nf+1)/2) * W/nf * 0.29'" 
pd="'2*int((nf+1)/2) * (W/nf + 0.29)'"
as="'int((nf+2)/2) * W/nf * 0.29'" 
ps="'2*int((nf+2)/2) * (W/nf + 0.29)'"
nrd="'0.29 / W'" nrs="'0.29 / W'"
sa=0 sb=0 sd=0
model=pfet_01v8
spiceprefix=X
}
C {sky130_fd_pr/pfet_01v8.sym} 730 -870 0 1 {name=MP17
*W= 8
W = \{w_MP2\}
*L= 4
L = \{l_MP2\}
nf=1
mult=1
ad="'int((nf+1)/2) * W/nf * 0.29'" 
pd="'2*int((nf+1)/2) * (W/nf + 0.29)'"
as="'int((nf+2)/2) * W/nf * 0.29'" 
ps="'2*int((nf+2)/2) * (W/nf + 0.29)'"
nrd="'0.29 / W'" nrs="'0.29 / W'"
sa=0 sb=0 sd=0
model=pfet_01v8
spiceprefix=X
}
C {sky130_fd_pr/pfet_01v8.sym} 940 -890 0 0 {name=MP18
*W=5
W = \{w_MP3\}
*L=4
L = \{l_MP3\}
nf=1
mult=1
ad="'int((nf+1)/2) * W/nf * 0.29'" 
pd="'2*int((nf+1)/2) * (W/nf + 0.29)'"
as="'int((nf+2)/2) * W/nf * 0.29'" 
ps="'2*int((nf+2)/2) * (W/nf + 0.29)'"
nrd="'0.29 / W'" nrs="'0.29 / W'"
sa=0 sb=0 sd=0
model=pfet_01v8
spiceprefix=X
}
C {sky130_fd_pr/pfet_01v8.sym} 940 -780 0 0 {name=MP19
*W=5
W = \{w_MP4\}
L = \{l_MP4\}
*L=5
nf=1
mult=1
ad="'int((nf+1)/2) * W/nf * 0.29'" 
pd="'2*int((nf+1)/2) * (W/nf + 0.29)'"
as="'int((nf+2)/2) * W/nf * 0.29'" 
ps="'2*int((nf+2)/2) * (W/nf + 0.29)'"
nrd="'0.29 / W'" nrs="'0.29 / W'"
sa=0 sb=0 sd=0
model=pfet_01v8
spiceprefix=X
}
C {sky130_fd_pr/nfet_01v8.sym} 470 -560 0 1 {name=MN17
*W=5
W = \{w_MN1\}
*L=0.5
L = \{l_MN1\}
nf=1
mult=1
ad="'int((nf+1)/2) * W/nf * 0.29'" 
pd="'2*int((nf+1)/2) * (W/nf + 0.29)'"
as="'int((nf+2)/2) * W/nf * 0.29'" 
ps="'2*int((nf+2)/2) * (W/nf + 0.29)'"
nrd="'0.29 / W'" nrs="'0.29 / W'"
sa=0 sb=0 sd=0
model=nfet_01v8
spiceprefix=X
}
C {sky130_fd_pr/nfet_01v8.sym} 690 -560 0 0 {name=MN18
*W=5
W = \{w_MN2\}
*L=0.5
L = \{l_MN2\}
nf=1
mult=1
ad="'int((nf+1)/2) * W/nf * 0.29'" 
pd="'2*int((nf+1)/2) * (W/nf + 0.29)'"
as="'int((nf+2)/2) * W/nf * 0.29'" 
ps="'2*int((nf+2)/2) * (W/nf + 0.29)'"
nrd="'0.29 / W'" nrs="'0.29 / W'"
sa=0 sb=0 sd=0
model=nfet_01v8
spiceprefix=X
}
C {sky130_fd_pr/nfet_01v8.sym} 940 -560 0 0 {name=MN19
*W=3
W = \{w_MN3\}
*L=0.5
L = \{l_MN3\}
nf=1
mult=1
ad="'int((nf+1)/2) * W/nf * 0.29'" 
pd="'2*int((nf+1)/2) * (W/nf + 0.29)'"
as="'int((nf+2)/2) * W/nf * 0.29'" 
ps="'2*int((nf+2)/2) * (W/nf + 0.29)'"
nrd="'0.29 / W'" nrs="'0.29 / W'"
sa=0 sb=0 sd=0
model=nfet_01v8
spiceprefix=X
}
C {sky130_fd_pr/nfet_01v8.sym} 940 -670 0 0 {name=MN20
*W=2
W = \{w_MN4\}
*L=5
L = \{l_MN4\}
nf=1
mult=1
ad="'int((nf+1)/2) * W/nf * 0.29'" 
pd="'2*int((nf+1)/2) * (W/nf + 0.29)'"
as="'int((nf+2)/2) * W/nf * 0.29'" 
ps="'2*int((nf+2)/2) * (W/nf + 0.29)'"
nrd="'0.29 / W'" nrs="'0.29 / W'"
sa=0 sb=0 sd=0
model=nfet_01v8
spiceprefix=X
}
C {devices/lab_pin.sym} 380 -890 0 0 {name=p25 sig_type=std_logic lab=VCONT}
C {sky130_fd_pr/nfet_01v8.sym} -1660 -40 0 0 {name=M2
W=\{w_buf\}
L=\{l_buf\}
nf=1
mult=\{mult\}
ad="'int((nf+1)/2) * W/nf * 0.29'" 
pd="'2*int((nf+1)/2) * (W/nf + 0.29)'"
as="'int((nf+2)/2) * W/nf * 0.29'" 
ps="'2*int((nf+2)/2) * (W/nf + 0.29)'"
nrd="'0.29 / W'" nrs="'0.29 / W'"
sa=0 sb=0 sd=0
model=nfet_01v8
spiceprefix=X
}
C {sky130_fd_pr/pfet_01v8.sym} -1660 -210 0 0 {name=M1
W=\{w_buf\}
L=\{l_buf\}
nf=1
mult=\{mult*3\}
ad="'int((nf+1)/2) * W/nf * 0.29'" 
pd="'2*int((nf+1)/2) * (W/nf + 0.29)'"
as="'int((nf+2)/2) * W/nf * 0.29'" 
ps="'2*int((nf+2)/2) * (W/nf + 0.29)'"
nrd="'0.29 / W'" nrs="'0.29 / W'"
sa=0 sb=0 sd=0
model=pfet_01v8
spiceprefix=X
}
C {devices/lab_pin.sym} -1470 -260 1 0 {name=p2 sig_type=std_logic lab=VDD}
C {devices/lab_pin.sym} -1640 40 3 0 {name=p3 sig_type=std_logic lab=VSS}
C {devices/lab_pin.sym} -1340 -110 1 0 {name=p8 sig_type=std_logic lab=Vo}
C {capa.sym} -1340 -60 0 0 {name=C1
m=1
value=\{Co\}
footprint=1206
device="ceramic capacitor"}
C {sky130_fd_pr/nfet_01v8.sym} -1490 -40 0 0 {name=M3
W=\{w_buf\}
L=\{l_buf\}
nf=1
mult=\{mult\}
ad="'int((nf+1)/2) * W/nf * 0.29'" 
pd="'2*int((nf+1)/2) * (W/nf + 0.29)'"
as="'int((nf+2)/2) * W/nf * 0.29'" 
ps="'2*int((nf+2)/2) * (W/nf + 0.29)'"
nrd="'0.29 / W'" nrs="'0.29 / W'"
sa=0 sb=0 sd=0
model=nfet_01v8
spiceprefix=X
}
C {sky130_fd_pr/pfet_01v8.sym} -1490 -210 0 0 {name=M4
W=\{w_buf\}
L=\{l_buf\}
nf=1
mult=\{mult*3\}
ad="'int((nf+1)/2) * W/nf * 0.29'" 
pd="'2*int((nf+1)/2) * (W/nf + 0.29)'"
as="'int((nf+2)/2) * W/nf * 0.29'" 
ps="'2*int((nf+2)/2) * (W/nf + 0.29)'"
nrd="'0.29 / W'" nrs="'0.29 / W'"
sa=0 sb=0 sd=0
model=pfet_01v8
spiceprefix=X
}
C {devices/lab_pin.sym} -1640 -260 1 0 {name=p9 sig_type=std_logic lab=VDD}
C {code.sym} -1220 -400 0 0 {name=MODEL only_toplevel=true spice_ignore=false
format="tcleval( @value )"
value="
.lib /opt/pdks/sky130A/libs.tech/ngspice/sky130.lib.spice tt
*.lib /opt/pdks/sky130A/libs.tech/ngspice/sky130.lib.spice ss
*.lib /opt/pdks/sky130A/libs.tech/ngspice/sky130.lib.spice ff
*.lib /opt/pdks/sky130A/libs.tech/ngspice/sky130.lib.spice sf
*.lib /opt/pdks/sky130A/libs.tech/ngspice/sky130.lib.spice fs
"}
C {code.sym} -1220 -250 0 0 {name=SimParameters only_toplevel=true spice_ignore=false
format="tcleval( @value )"
value="
.param Co = 1p
.param mult = 1
.param w_buf = 1
.param l_buf = 0.15

.param vvcont = 0.9

vvdd vdd 0 dc 1.8
vvss vss 0 0
*vvcont VCONT 0 dc 0
*vvcont2 VCONT2 0 dc 0
*.option temp = 200
.ic v(V_1) = 0
.ic v(V_2) = 1.8
.save v(V_1) v(Vo)

.param SimTime =  40u
.csparam SimTime =\{Simtime\}
.csparam Tmargin = 15u


"}
C {devices/code.sym} -1070 -400 0 0 {name=SweepVcont only_toplevel=false spice_ignore=true
value="

.tran 10n \{SimTime\}
.csparam start = 10
.control
let Vtarg = 0.9
compose vin_var start=0 stop=0.8 step=0.1

let strt = 0
let stp = 0.8
let step = 0.1
let len2 = 1 + (stp-strt)/step
let f_sweep = vector(len2)
let index = 0
foreach val $&vin_var
	alter vcont $val
	let f_sum = 0
	let t_act = 0
	let period_cont = 1
	let period_cont2 = 2
	run
	while t_act le SimTime - Tmargin
		meas tran t_rise WHEN v(Vo) = \{Vtarg\} RISE = \{period_cont\}
		let t_act = t_rise
		*print t_act SimTime period_cont
		meas tran T TRIG v(Vo) VAL = \{Vtarg\} RISE = \{period_cont\} TARG v(Vo) VAL = \{Vtarg\}  RISE = \{period_cont2\}
		let f =1/T
		let f_sum = f_sum + f
		let period_cont = period_cont + 1
		let period_cont2 = period_cont2 + 1
	end
	*wrdata ../../sim_data/data_VCO_vto1p1.txt tran1.v(V_1) tran2.v(V_1) tran3.v(V_1) tran4.v(V_1) tran5.v(V_1) tran6.v(V_1) tran7.v(V_1) tran8.v(V_1) tran9.v(V_1) tran10.v(V_1) tran11.v(V_1) tran12.v(V_1) tran13.v(V_1) tran14.v(V_1) tran15.v(V_1) tran16.v(V_1) tran17.v(V_1)
	let f_avg = f_sum/(period_cont-1)
	let f_sweep[index] = f_avg
	let index = index +1
end
plot tran1.v(Vo) 
plot tran9.v(Vo)
print f_sweep
plot f_sweep vs vin_var
.endc
"}
C {code.sym} -1070 -250 0 0 {name=VCO_param1 only_toplevel=true spice_ignore=false
format="tcleval( @value )"
value="

.param w_MP1 = 0.5
.param l_MP1 = 7
.param w_MP2 = 8
.param l_MP2 = 4
.param w_MP3 = 5
.param l_MP3 = 4
.param w_MP4 = 3
.param l_MP4 = 0.15

.param w_MN1 = 5
.param l_MN1 = 0.5
.param w_MN2 = 5
.param l_MN2 = 0.5
.param w_MN3 = 3
.param l_MN3 = 0.5
.param w_MN4 = 1
.param l_MN4 = 0.15


"}
C {lab_wire.sym} -2530 -580 0 0 {name=p10 sig_type=std_logic lab=VCN}
C {lab_wire.sym} -2280 -880 0 0 {name=p14 sig_type=std_logic lab=VCP}
C {ammeter.sym} -2670 -780 0 0 {name=VIcont savecurrent=true spice_ignore=0}
C {devices/code.sym} -930 -400 0 0 {name=DCSim only_toplevel=false spice_ignore=false
value="
.save all
.csparam start = 10
.control
alter Vg1 = 0
dc Vcont 0 1 0.01 
let Icont = i(VIcont)
*let Iout = i(VIout)
let VCN = v(VCN)
let VCP = v(VCP)
let  Vin = v(Vin)

plot Icont vs Vcont
*plot Iout vs VCP
plot VCP vs Vcont
plot VCN vs Vcont
*plot Vin vs Vcont

.endc
"}
